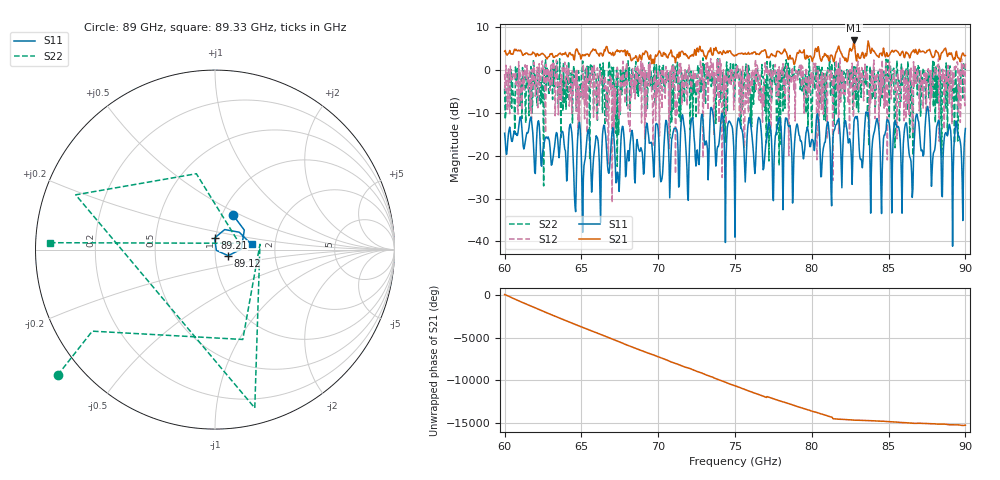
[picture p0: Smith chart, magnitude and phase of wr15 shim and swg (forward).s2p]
!Created with skrf (http://scikit-rf.org).
# GHz S RI R 50.0
!freq ReS11 ImS11 ReS21 ImS21 ReS12 ImS12 ReS22 ImS22
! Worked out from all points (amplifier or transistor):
!   721 points, 60 GHz to 90 GHz, reference 50 ohm
!   highest |S21| = 6.9 dB at 82.75 GHz (marker M1)
!   |S21| within 3 dB of that: 86.91 GHz to 87.75 GHz (834 MHz wide, 0.955 % of centre) (the widest 1 of 59)
!   unconditionally stable (mu >= 1): 60.32906 GHz to 60.33581 GHz; 61.10349 GHz to 61.1389 GHz; 86.52392 GHz to 86.61093 GHz (the widest 3 of 27)
!   at 65 GHz: K = 0.55, MSG = 3.9 dB, |S12| = -4.9 dB
!   at 75 GHz: K = 0.86, MSG = 2.6 dB, |S12| = -1.7 dB
!   at 90 GHz: K = 0.81, MSG = 0.9 dB, |S12| = 1.6 dB
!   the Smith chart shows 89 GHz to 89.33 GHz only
!   S11 on the Smith chart (normalised r, x): 89 GHz: 1.12, +0.46; 89.12 GHz: 1.16, -0.08; 89.21 GHz: 0.99, +0.13; 89.33 GHz: 1.51, +0.09
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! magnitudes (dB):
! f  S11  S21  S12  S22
! 60 GHz  -14.7  4.4  -0.9  -4.3
! 65 GHz  -20.9  3.0  -4.9  -0.8
! 66.5 GHz  -13.0  4.8  -4.1  -0.1
! 67.38 GHz  -23.9  4.4  0.0  -0.4
! 67.67 GHz  -13.1  4.4  0.0  -0.1
! 70 GHz  -13.9  3.9  0.0  -0.7
! 71.62 GHz  -11.3  4.1  -2.6  -0.9
! 71.92 GHz  -29.1  3.1  -5.2  -1.9
! 73.5 GHz  -9.0  3.6  -1.7  -2.2
! 75 GHz  -39.0  3.5  -1.7  -4.2
! 80 GHz  -16.2  2.6  -3.0  -14.6
! 82.75 GHz  -11.9  6.9  -7.0  0.8
! 84.25 GHz  -11.3  3.3  -1.0  -1.2
! 84.54 GHz  -33.5  4.0  -5.6  -3.3
! 85 GHz  -12.0  3.4  -1.6  1.0
! 86.5 GHz  -24.0  4.2  -2.1  -7.6
! 86.83 GHz  -10.2  4.1  -0.3  -1.4
! 89 GHz  -13.2  3.7  -0.6  1.0
! 89.12 GHz  -21.9  3.5  -12.5  -12.0
! 89.21 GHz  -23.8  2.5  -4.0  -1.6
! 89.33 GHz  -13.7  2.7  -0.1  -0.7
! 90 GHz  -13.6  3.4  1.6  -0.2
